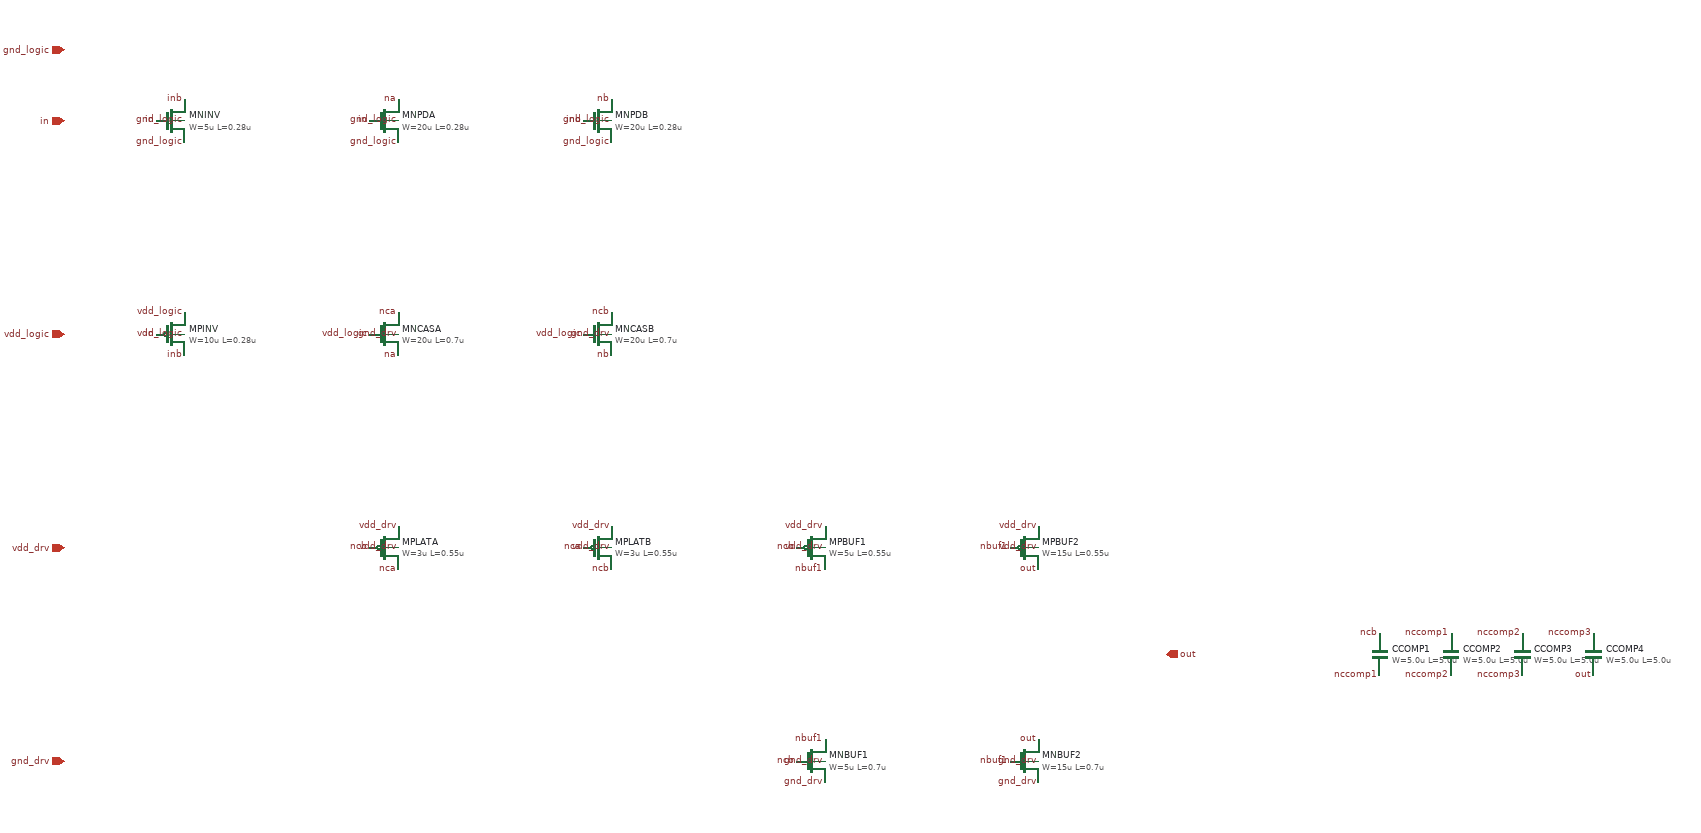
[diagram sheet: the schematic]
v {xschem version=3.4.7 file_version=1.2
* level_shifter -- cascode/clamped 3.3V-logic to 5V/6V-drive-rail level shifter
* spec/gate-driver.md sec4; see design/level-shifter-partition.md for the domain
* partition and cascode-bias derivation. Generated by hand per xschem text format,
* net connectivity verified via `xschem -x -n -s` (see PR description).
*
* CCOMP1..CCOMP4 (issues #155/#192, spec/decision-records/0007 + 0014): a
* ~12-15 fF feedforward compensation capacitor from `out` (the inter-cell
* net IN_DRV at the block level) to `ncb`, realized as FOUR series
* cap_mim_2f0_m4m5_noshield devices at the DRM minimum 5.0um x 5.0um.
* Mitigates the gate-drive-feedthrough overshoot onto IN_DRV characterized
* in spec/decision-records/0006 -- `ncb` collapses during exactly the window
* `nbuf1` rises and injects charge through XMPBUF2/XMNBUF2's C_gd, so its
* coupled charge cancels the feedthrough.
* Sized at the small end of decision record 0006's characterized effective
* range (10-100 fF) rather than the middle: measured evidence gathered
* while implementing issue #155 showed capacitance above ~15-20 fF starts
* feeding back through the cascode (XMNCASB) into the thin-oxide na/nb
* nodes, eroding decision records 0002/0003's margin there -- see
* spec/decision-records/0007 for the measured tradeoff.
* WHY FOUR IN SERIES (decision record 0014, issue #192): gf180mcuD fixes the
* MIM density at 2.0 fF/um2 (nodeinfo.json "MIM_2P0"; the PDK's own
* libs.tech/klayout/lvs/run_lvs.py binds variant=D to mim_cap=2; its magic
* techfile and netgen setup define exactly one MIM device,
* cap_mim_2f0_m4m5_noshield), so decision record 0007's cap_mim_1f0_* is not
* a fabricable device here; and DRM rule MIMTM.8a sets a 25um2 minimum MIM
* area, so the SMALLEST single MIM this process can build is 54.5 fF (tt) --
* four times too large. Four minimum-area devices in series give 13.63 fF
* (tt), the least-area MIM realization that preserves both ratified bounds.
* Does not remove the need for decision record 0006's Exception 3 (IN_DRV's
* quiescent high level is VDD_DRV by construction, zero margin at the 6V
* stretch rail regardless of shaping) -- narrows its bound only.
}
G {}
K {}
V {}
S {}
E {}
C {symbols/nfet_03v3.sym} 0 0 0 0 {name=MNINV
L=0.28u
W=5u
model=nfet_03v3
spiceprefix=X}
C {devices/lab_pin.sym} 20 -30 0 0 {name=l1 sig_type=std_logic lab=inb}
C {devices/lab_pin.sym} -20 0 0 0 {name=l2 sig_type=std_logic lab=in}
C {devices/lab_pin.sym} 20 30 0 0 {name=l3 sig_type=std_logic lab=gnd_logic}
C {devices/lab_pin.sym} 20 0 0 0 {name=l4 sig_type=std_logic lab=gnd_logic}
C {symbols/pfet_03v3.sym} 0 300 0 0 {name=MPINV
L=0.28u
W=10u
model=pfet_03v3
spiceprefix=X}
C {devices/lab_pin.sym} 20 330 0 0 {name=l5 sig_type=std_logic lab=inb}
C {devices/lab_pin.sym} -20 300 0 0 {name=l6 sig_type=std_logic lab=in}
C {devices/lab_pin.sym} 20 270 0 0 {name=l7 sig_type=std_logic lab=vdd_logic}
C {devices/lab_pin.sym} 20 300 0 0 {name=l8 sig_type=std_logic lab=vdd_logic}
C {symbols/nfet_03v3.sym} 300 0 0 0 {name=MNPDA
L=0.28u
W=20u
model=nfet_03v3
spiceprefix=X}
C {devices/lab_pin.sym} 320 -30 0 0 {name=l9 sig_type=std_logic lab=na}
C {devices/lab_pin.sym} 280 0 0 0 {name=l10 sig_type=std_logic lab=in}
C {devices/lab_pin.sym} 320 30 0 0 {name=l11 sig_type=std_logic lab=gnd_logic}
C {devices/lab_pin.sym} 320 0 0 0 {name=l12 sig_type=std_logic lab=gnd_logic}
C {symbols/nfet_03v3.sym} 600 0 0 0 {name=MNPDB
L=0.28u
W=20u
model=nfet_03v3
spiceprefix=X}
C {devices/lab_pin.sym} 620 -30 0 0 {name=l13 sig_type=std_logic lab=nb}
C {devices/lab_pin.sym} 580 0 0 0 {name=l14 sig_type=std_logic lab=inb}
C {devices/lab_pin.sym} 620 30 0 0 {name=l15 sig_type=std_logic lab=gnd_logic}
C {devices/lab_pin.sym} 620 0 0 0 {name=l16 sig_type=std_logic lab=gnd_logic}
C {symbols/nfet_06v0.sym} 300 300 0 0 {name=MNCASA
L=0.7u
W=20u
model=nfet_06v0
spiceprefix=X}
C {devices/lab_pin.sym} 320 270 0 0 {name=l17 sig_type=std_logic lab=nca}
C {devices/lab_pin.sym} 280 300 0 0 {name=l18 sig_type=std_logic lab=vdd_logic}
C {devices/lab_pin.sym} 320 330 0 0 {name=l19 sig_type=std_logic lab=na}
C {devices/lab_pin.sym} 320 300 0 0 {name=l20 sig_type=std_logic lab=gnd_drv}
C {symbols/nfet_06v0.sym} 600 300 0 0 {name=MNCASB
L=0.7u
W=20u
model=nfet_06v0
spiceprefix=X}
C {devices/lab_pin.sym} 620 270 0 0 {name=l21 sig_type=std_logic lab=ncb}
C {devices/lab_pin.sym} 580 300 0 0 {name=l22 sig_type=std_logic lab=vdd_logic}
C {devices/lab_pin.sym} 620 330 0 0 {name=l23 sig_type=std_logic lab=nb}
C {devices/lab_pin.sym} 620 300 0 0 {name=l24 sig_type=std_logic lab=gnd_drv}
C {symbols/pfet_06v0.sym} 300 600 0 0 {name=MPLATA
L=0.55u
W=3u
model=pfet_06v0
spiceprefix=X}
C {devices/lab_pin.sym} 320 630 0 0 {name=l25 sig_type=std_logic lab=nca}
C {devices/lab_pin.sym} 280 600 0 0 {name=l26 sig_type=std_logic lab=ncb}
C {devices/lab_pin.sym} 320 570 0 0 {name=l27 sig_type=std_logic lab=vdd_drv}
C {devices/lab_pin.sym} 320 600 0 0 {name=l28 sig_type=std_logic lab=vdd_drv}
C {symbols/pfet_06v0.sym} 600 600 0 0 {name=MPLATB
L=0.55u
W=3u
model=pfet_06v0
spiceprefix=X}
C {devices/lab_pin.sym} 620 630 0 0 {name=l29 sig_type=std_logic lab=ncb}
C {devices/lab_pin.sym} 580 600 0 0 {name=l30 sig_type=std_logic lab=nca}
C {devices/lab_pin.sym} 620 570 0 0 {name=l31 sig_type=std_logic lab=vdd_drv}
C {devices/lab_pin.sym} 620 600 0 0 {name=l32 sig_type=std_logic lab=vdd_drv}
C {symbols/pfet_06v0.sym} 900 600 0 0 {name=MPBUF1
L=0.55u
W=5u
model=pfet_06v0
spiceprefix=X}
C {devices/lab_pin.sym} 920 630 0 0 {name=l33 sig_type=std_logic lab=nbuf1}
C {devices/lab_pin.sym} 880 600 0 0 {name=l34 sig_type=std_logic lab=ncb}
C {devices/lab_pin.sym} 920 570 0 0 {name=l35 sig_type=std_logic lab=vdd_drv}
C {devices/lab_pin.sym} 920 600 0 0 {name=l36 sig_type=std_logic lab=vdd_drv}
C {symbols/nfet_06v0.sym} 900 900 0 0 {name=MNBUF1
L=0.7u
W=5u
model=nfet_06v0
spiceprefix=X}
C {devices/lab_pin.sym} 920 870 0 0 {name=l37 sig_type=std_logic lab=nbuf1}
C {devices/lab_pin.sym} 880 900 0 0 {name=l38 sig_type=std_logic lab=ncb}
C {devices/lab_pin.sym} 920 930 0 0 {name=l39 sig_type=std_logic lab=gnd_drv}
C {devices/lab_pin.sym} 920 900 0 0 {name=l40 sig_type=std_logic lab=gnd_drv}
C {symbols/pfet_06v0.sym} 1200 600 0 0 {name=MPBUF2
L=0.55u
W=15u
model=pfet_06v0
spiceprefix=X}
C {devices/lab_pin.sym} 1220 630 0 0 {name=l41 sig_type=std_logic lab=out}
C {devices/lab_pin.sym} 1180 600 0 0 {name=l42 sig_type=std_logic lab=nbuf1}
C {devices/lab_pin.sym} 1220 570 0 0 {name=l43 sig_type=std_logic lab=vdd_drv}
C {devices/lab_pin.sym} 1220 600 0 0 {name=l44 sig_type=std_logic lab=vdd_drv}
C {symbols/nfet_06v0.sym} 1200 900 0 0 {name=MNBUF2
L=0.7u
W=15u
model=nfet_06v0
spiceprefix=X}
C {devices/lab_pin.sym} 1220 870 0 0 {name=l45 sig_type=std_logic lab=out}
C {devices/lab_pin.sym} 1180 900 0 0 {name=l46 sig_type=std_logic lab=nbuf1}
C {devices/lab_pin.sym} 1220 930 0 0 {name=l47 sig_type=std_logic lab=gnd_drv}
C {devices/lab_pin.sym} 1220 900 0 0 {name=l48 sig_type=std_logic lab=gnd_drv}
C {devices/ipin.sym} -150 0 0 0 {name=p_in lab=in}
C {devices/ipin.sym} -150 300 0 0 {name=p_vddl lab=vdd_logic}
C {devices/ipin.sym} -150 -100 0 0 {name=p_gndl lab=gnd_logic}
C {devices/ipin.sym} -150 600 0 0 {name=p_vddd lab=vdd_drv}
C {devices/ipin.sym} -150 900 0 0 {name=p_gndd lab=gnd_drv}
C {devices/opin.sym} 1400 750 0 0 {name=p_out lab=out}
C {symbols/cap_mim_2f0fF.sym} 1700 750 0 0 {name=CCOMP1
W=5.0u
L=5.0u
model=cap_mim_2f0_m4m5_noshield
spiceprefix=X
m=1}
C {devices/lab_pin.sym} 1700 720 0 0 {name=l49 sig_type=std_logic lab=ncb}
C {devices/lab_pin.sym} 1700 780 0 0 {name=l50 sig_type=std_logic lab=nccomp1}
C {symbols/cap_mim_2f0fF.sym} 1800 750 0 0 {name=CCOMP2
W=5.0u
L=5.0u
model=cap_mim_2f0_m4m5_noshield
spiceprefix=X
m=1}
C {devices/lab_pin.sym} 1800 720 0 0 {name=l51 sig_type=std_logic lab=nccomp1}
C {devices/lab_pin.sym} 1800 780 0 0 {name=l52 sig_type=std_logic lab=nccomp2}
C {symbols/cap_mim_2f0fF.sym} 1900 750 0 0 {name=CCOMP3
W=5.0u
L=5.0u
model=cap_mim_2f0_m4m5_noshield
spiceprefix=X
m=1}
C {devices/lab_pin.sym} 1900 720 0 0 {name=l53 sig_type=std_logic lab=nccomp2}
C {devices/lab_pin.sym} 1900 780 0 0 {name=l54 sig_type=std_logic lab=nccomp3}
C {symbols/cap_mim_2f0fF.sym} 2000 750 0 0 {name=CCOMP4
W=5.0u
L=5.0u
model=cap_mim_2f0_m4m5_noshield
spiceprefix=X
m=1}
C {devices/lab_pin.sym} 2000 720 0 0 {name=l55 sig_type=std_logic lab=nccomp3}
C {devices/lab_pin.sym} 2000 780 0 0 {name=l56 sig_type=std_logic lab=out}
